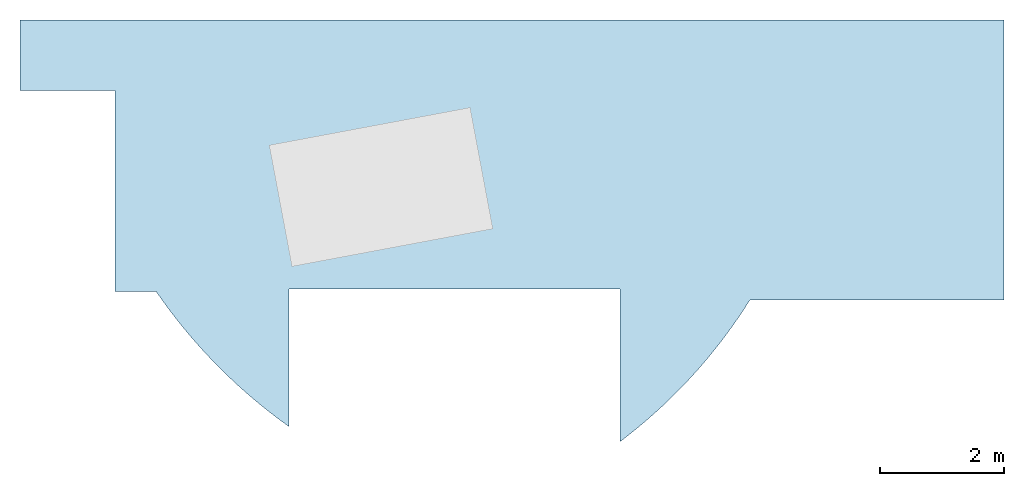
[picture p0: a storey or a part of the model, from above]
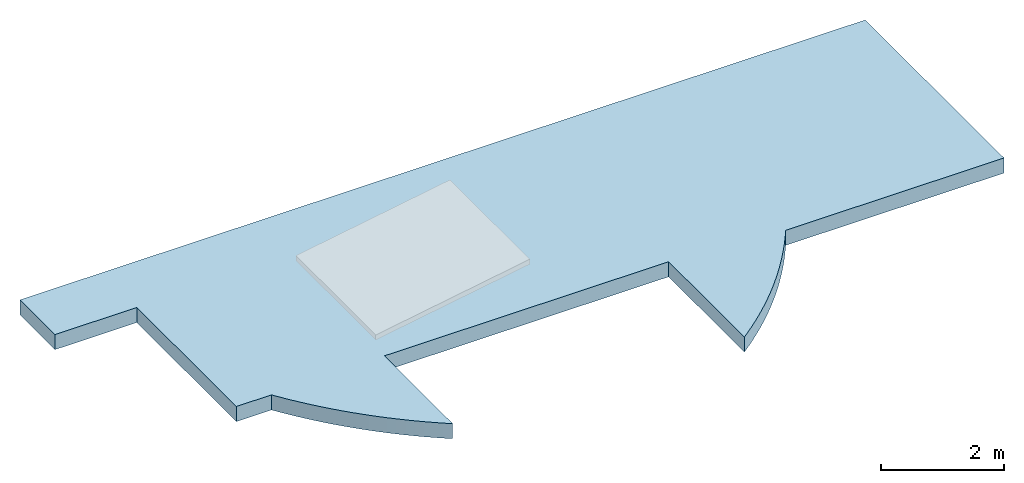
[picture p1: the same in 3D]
Properties of the parts of a building model (IFC4)

# File
Description: no view
File name: 20251114 LONDRES 55 HCB IFC.ifc
Time: 2025-11-14T18:05:01
Author: tecnic5
Organization: No Organization
Written by: ODA SDAI 25.4
Authorization: Usuari

# IfcBuildingStorey (22)
Name | In
PLANTA COBERTA | HABITATGE PLURIFAMILIAR | Elevation: 24.37 m
NOU | PLANTA COBERTA
PLANTA SOTACOBERTA | HABITATGE PLURIFAMILIAR | Elevation: 21.2 m
NOU | PLANTA SOTACOBERTA
PLANTA CINQUENA | HABITATGE PLURIFAMILIAR | Elevation: 18.29 m
NOU | PLANTA CINQUENA
PLANTA QUARTA | HABITATGE PLURIFAMILIAR | Elevation: 15.28 m
NOU | PLANTA QUARTA
PLANTA TERCERA | HABITATGE PLURIFAMILIAR | Elevation: 12.27 m
NOU | PLANTA TERCERA
PLANTA SEGONA | HABITATGE PLURIFAMILIAR | Elevation: 9.26 m
NOU | PLANTA SEGONA
PLANTA PRIMERA | HABITATGE PLURIFAMILIAR | Elevation: 6.25 m
NOU | PLANTA PRIMERA
PLANTA ALTELL | HABITATGE PLURIFAMILIAR | Elevation: 3.35 m
NOU | PLANTA ALTELL
PLANTA BAIXA | HABITATGE PLURIFAMILIAR | Elevation: 0 m
NOU | PLANTA BAIXA
PLANTA SOTERRANI -1 | HABITATGE PLURIFAMILIAR | Elevation: -3.37 m
NOU | PLANTA SOTERRANI -1
PLANTA SOTERRANI -2 | HABITATGE PLURIFAMILIAR | Elevation: -6.3 m
NOU | PLANTA SOTERRANI -2

# IfcBeam (2)
In: NOU
HCB_Identificacio - HCB_I1-CodiGuBIMclass: 20.20.20.20; HCB_I2-DescripcioBIMclass: Jàsseres; HCB_I3-TipusNom: Jàssera; HCB_I4-Subsistema: ARQ
Pset_BeamCommon - Status: EXISTING
Name
Jàssera PSC
Jàssera PS-2

# IfcBuildingElementProxy (38)
In: NOU
Name | HCB_I1-CodiGuBIMclass | HCB_I2-DescripcioBIMclass | HCB_I3-TipusNom | HCB_I4-Subsistema | Status
3 x Mirall P5 | 60.20.10.60 | Miralls | Mirall | ARQ | EXISTING
Porta P5 | 40.10.10.40 | Fusteria interior | FUS_Porta | ARQ | NEW
3 x Mirall P4 | 60.20.10.60 | Miralls | Mirall | ARQ | EXISTING
Porta P4 | 40.10.10.40 | Fusteria interior | FUS_Porta | ARQ | NEW
3 x Mirall P3 | 60.20.10.60 | Miralls | Mirall | ARQ | EXISTING
Porta P3 | 40.10.10.40 | Fusteria interior | FUS_Porta | ARQ | NEW
3 x Mirall P2 | 60.20.10.60 | Miralls | Mirall | ARQ | EXISTING
2 x Porta P2 | 40.10.10.40 | Fusteria interior | FUS_Porta | ARQ | NEW
2 x Taula redona 1.2m
3 x Mirall P1 | 60.20.10.60 | Miralls | Mirall | ARQ | EXISTING
2 x Inodor P1 | 60.10.10.10 | Inodors | Inodor | ARQ | EXISTING
Porta exterior P1 | 30.10.20.20 | Portes de façanes | Porta de façana | ARQ | EXISTING
Porta P1 | 40.10.10.40 | Fusteria interior | FUS_Porta | ARQ | NEW
4 x Mirall PA | 60.20.10.60 | Miralls | Mirall | ARQ | EXISTING
3 x Nuevo macro (8)
Porta PA | 40.10.10.40 | Fusteria interior | FUS_Porta | ARQ | NEW
2 x Mirall PB | 60.20.10.60 | Miralls | Mirall | ARQ | EXISTING
Mirall PB | 60.20.10.60 | Miralls | Mirall | ARQ | NEW
Porta PB | 40.10.10.40 | Fusteria interior | FUS_Porta | ARQ | NEW

# IfcColumn (159)
In: NOU
PredefinedType: COLUMN
HCB_Identificacio - HCB_I1-CodiGuBIMclass: 20.20.10.10; HCB_I2-DescripcioBIMclass: Pilars; HCB_I3-TipusNom: Pilar; HCB_I4-Subsistema: ARQ
Pset_ColumnCommon - Status: EXISTING
Name
17 x Pilar P5
17 x Pilar P4
17 x Pilar P3
17 x Pilar P2
17 x Pilar P1
20 x Pilar PA
18 x Pilar PB
18 x Pilar PS-1
18 x Pilar PS-2

# IfcDoor (203)
In: NOU
PredefinedType: DOOR; OperationType: USERDEFINED
AllplanQuantities - GlassSurface: 0; HeightWindowSillOutside: 0; HeightWindowSillInside: 0; OffsetOpeningBottom: 0; OffsetOpeningTop: 0; OffsetOpeningLeft: 0; OffsetOpeningRight: 0; DeductionOpeningBottom: 0
HCB_Identificacio - HCB_I4-Subsistema: ARQ
Name | OverallHeight (m) | OverallWidth (m) | DeductionOpeningLeft = DeductionOpeningRight | DeductionOpeningTop | HCB_I1-CodiGuBIMclass | HCB_I2-DescripcioBIMclass | HCB_I3-TipusNom | Status
Porta PSC | 2.15 | 0.94 | 70 | 70 | 30.10.20.20 | Portes de façanes | Porta de façana | EXISTING
Porta PSC | 2.15 | 0.91 | 70 | 70 | 40.10.10.40 | Fusteria interior | FUS_Porta | EXISTING
Porta PSC | 2.15 | 0.83 | 70 | 70 | 40.10.10.40 | Fusteria interior | FUS_Porta | EXISTING
Porta PSC | 2.15 | 0.85 | 70 | 70 | 40.10.10.40 | Fusteria interior | FUS_Porta | EXISTING
Porta PSC | 2.15 | 0.90716 | 70 | 70 | 30.10.20.20 | Portes de façanes | Porta de façana | EXISTING
Porta P5 | 2.15 | 1.7991 | 70 | 70 | 40.10.10.40 | Fusteria interior | FUS_Porta | EXISTING
Porta P5 | 2.15 | 1.7383 | 70 | 70 | 40.10.10.40 | Fusteria interior | FUS_Porta | EXISTING
Porta P5 | 2.15 | 1.33 | 70 | 70 | 40.10.10.40 | Fusteria interior | FUS_Porta | EXISTING
Porta P5 | 2.15 | 1.23 | 70 | 70 | 40.10.10.40 | Fusteria interior | FUS_Porta | EXISTING
Porta P5 | 2.15 | 0.85 | 70 | 70 | 40.10.10.40 | Fusteria interior | FUS_Porta | EXISTING
Porta P5 | 2.15 | 0.76332 | 50 | 50 | 40.10.10.40 | Fusteria interior | FUS_Porta | EXISTING
7 x Porta P5 | 2.15 | 0.94 | 70 | 70 | 40.10.10.40 | Fusteria interior | FUS_Porta | NEW
5 x Porta PA | 2.15 | 0.82267 | 30 | 30 | 40.10.10.40 | Fusteria interior | FUS_Porta | EXISTING
2 x Porta P4 | 2.15 | 0.44193 | 30 | 30 | 40.10.10.40 | Fusteria interior | FUS_Porta | NEW
Porta P5 | 2.15 | 0.74152 | 70 | 70 | 40.10.10.40 | Fusteria interior | FUS_Porta | NEW
Porta P5 | 2.15 | 0.73897 | 70 | 70 | 40.10.10.40 | Fusteria interior | FUS_Porta | NEW
Porta P5 | 2.15 | 1 | 70 | 70 | 40.10.10.40 | Fusteria interior | FUS_Porta | EXISTING
Porta P5 | 2.15 | 0.9 | 0 | 0 | 40.10.10.40 | Fusteria interior | FUS_Porta | NEW
Porta P5 | 2.15 | 1.02087 | 70 | 70 | 40.10.10.40 | Fusteria interior | FUS_Porta | NEW
Porta P4 | 2.15 | 1.73842 | 70 | 70 | 40.10.10.40 | Fusteria interior | FUS_Porta | EXISTING
Porta P4 | 2.15 | 1.32905 | 70 | 70 | 40.10.10.40 | Fusteria interior | FUS_Porta | EXISTING
Porta P4 | 2.15 | 1.23 | 70 | 70 | 40.10.10.40 | Fusteria interior | FUS_Porta | EXISTING
Porta P4 | 2.15 | 1.7991 | 70 | 70 | 40.10.10.40 | Fusteria interior | FUS_Porta | EXISTING
Porta P4 | 2.15 | 0.76751 | 50 | 50 | 40.10.10.40 | Fusteria interior | FUS_Porta | EXISTING
Porta P4 | 2.15 | 0.84771 | 70 | 70 | 40.10.10.40 | Fusteria interior | FUS_Porta | EXISTING
Porta P4 | 2.15 | 0.73897 | 70 | 70 | 40.10.10.40 | Fusteria interior | FUS_Porta | NEW
Porta P4 | 2.15 | 0.74 | 70 | 70 | 40.10.10.40 | Fusteria interior | FUS_Porta | NEW
Porta P4 | 2.15 | 1 | 70 | 70 | 40.10.10.40 | Fusteria interior | FUS_Porta | NEW
Porta P4 | 2.15 | 0.9 | 0 | 0 | 40.10.10.40 | Fusteria interior | FUS_Porta | NEW
Porta P4 | 2.15 | 1.02087 | 70 | 70 | 40.10.10.40 | Fusteria interior | FUS_Porta | NEW
Porta P4 | 2.15 | 0.94 | 70 | 70 | 40.10.10.40 | Fusteria interior | FUS_Porta | EXISTING
3 x Porta P4 | 2.15 | 0.94 | 70 | 70 | 40.10.10.40 | Fusteria interior | FUS_Porta | NEW
Porta P3 | 2.15 | 1.73983 | 70 | 70 | 40.10.10.40 | Fusteria interior | FUS_Porta | EXISTING
Porta P3 | 2.71 | 1.23 | 70 | 70 | 40.10.10.40 | Fusteria interior | FUS_Porta | EXISTING
Porta P3 | 2.15 | 1.7991 | 70 | 70 | 40.10.10.40 | Fusteria interior | FUS_Porta | EXISTING
Porta P3 | 2.71 | 0.85 | 70 | 70 | 40.10.10.40 | Fusteria interior | FUS_Porta | EXISTING
Porta P3 | 2.15 | 1.33 | 70 | 70 | 40.10.10.40 | Fusteria interior | FUS_Porta | EXISTING
Porta P3 | 2.15 | 0.76332 | 50 | 50 | 40.10.10.40 | Fusteria interior | FUS_Porta | EXISTING
Porta P3 | 2.15 | 0.99903 | 70 | 70 | 40.10.10.40 | Fusteria interior | FUS_Porta | NEW
Porta P3 | 2.71 | 0.77103 | 70 | 70 | 40.10.10.40 | Fusteria interior | FUS_Porta | NEW
Porta P3 | 2.15 | 0.74 | 70 | 70 | 40.10.10.40 | Fusteria interior | FUS_Porta | NEW
8 x Porta P3 | 2.15 | 0.94 | 70 | 70 | 40.10.10.40 | Fusteria interior | FUS_Porta | NEW
Porta P3 | 2.3 | 0.88801 | 70 | 70 | 40.10.10.40 | Fusteria interior | FUS_Porta | NEW
Porta P3 | 2.71 | 0.9 | 0 | 0 | 40.10.10.40 | Fusteria interior | FUS_Porta | NEW
Porta P3 | 2.15 | 1.02664 | 70 | 70 | 40.10.10.40 | Fusteria interior | FUS_Porta | NEW
Porta P2 | 2.71 | 0.85 | 70 | 70 | 40.10.10.40 | Fusteria interior | FUS_Porta | EXISTING
Porta P2 | 2.71 | 1.73983 | 70 | 70 | 40.10.10.40 | Fusteria interior | FUS_Porta | EXISTING
Porta P2 | 2.71 | 1.22594 | 70 | 70 | 40.10.10.40 | Fusteria interior | FUS_Porta | EXISTING
Porta P2 | 2.71 | 1.33 | 70 | 70 | 40.10.10.40 | Fusteria interior | FUS_Porta | EXISTING
Porta P2 | 2.3 | 1.60014 | 70 | 70 | 40.10.10.40 | Fusteria interior | FUS_Porta | EXISTING
Porta P2 | 2.71 | 0.8061 | 50 | 50 | 40.10.10.40 | Fusteria interior | FUS_Porta | EXISTING
11 x Porta P2 | 2.3 | 0.94 | 70 | 70 | 40.10.10.40 | Fusteria interior | FUS_Porta | NEW
Porta P2 | 2.71 | 0.7 | 70 | 70 | 40.10.10.40 | Fusteria interior | FUS_Porta | NEW
Porta P2 | 2.71 | 0.74 | 70 | 70 | 40.10.10.40 | Fusteria interior | FUS_Porta | NEW
Porta P2 | 2.71 | 0.99903 | 70 | 70 | 40.10.10.40 | Fusteria interior | FUS_Porta | NEW
Porta P2 | 2.15 | 0.44193 | 30 | 70 | 40.10.10.40 | Fusteria interior | FUS_Porta | NEW
Porta P2 | 2.71 | 0.79577 | 0 | 0 | 40.10.10.40 | Fusteria interior | FUS_Porta | NEW
Porta P2 | 2.71 | 1.02087 | 70 | 70 | 40.10.10.40 | Fusteria interior | FUS_Porta | NEW
Porta P1 | 2.15 | 0.82523 | 70 | 70 | 40.10.10.40 | Fusteria interior | FUS_Porta | EXISTING
Porta P1 | 2.15 | 0.76751 | 70 | 70 | 40.10.10.40 | Fusteria interior | FUS_Porta | EXISTING
Porta P1 | 2.15 | 1.60127 | 70 | 70 | 40.10.10.40 | Fusteria interior | FUS_Porta | EXISTING
Porta P1 | 2.15 | 0.79017 | 50 | 50 | 40.10.10.40 | Fusteria interior | FUS_Porta | EXISTING
Porta P1 | 2.15 | 0.85 | 70 | 70 | 40.10.10.40 | Fusteria interior | FUS_Porta | EXISTING
Porta P1 | 2.15 | 1.33311 | 70 | 70 | 40.10.10.40 | Fusteria interior | FUS_Porta | EXISTING
Porta P1 | 2.15 | 1.23 | 70 | 70 | 40.10.10.40 | Fusteria interior | FUS_Porta | EXISTING
Porta P1 | 2.15 | 1.74 | 70 | 70 | 40.10.10.40 | Fusteria interior | FUS_Porta | EXISTING
Porta exterior P1 | 2.19 | 0.99904 | 70 | 70 | 30.10.20.20 | Portes de façanes | Porta de façana | EXISTING
13 x Porta P1 | 2.15 | 0.94 | 70 | 70 | 40.10.10.40 | Fusteria interior | FUS_Porta | NEW
Porta P1 | 2.15 | 0.9 | 70 | 70 | 40.10.10.40 | Fusteria interior | FUS_Porta | NEW
Porta P1 | 2.3 | 0.94 | 70 | 70 | 40.10.10.40 | Fusteria interior | FUS_Porta | NEW
2 x Porta P1 | 2.15 | 0.74 | 70 | 70 | 40.10.10.40 | Fusteria interior | FUS_Porta | NEW
Porta P1 | 2.15 | 0.99903 | 70 | 70 | 40.10.10.40 | Fusteria interior | FUS_Porta | NEW
Porta P1 | 2.15 | 0.44193 | 30 | 30 | 40.10.10.40 | Fusteria interior | FUS_Porta | NEW
Porta P1 | 2.15 | 0.79405 | 0 | 0 | 40.10.10.40 | Fusteria interior | FUS_Porta | NEW
Porta PA | 2.1 | 1.12 | 70 | 70 | 40.10.10.40 | Fusteria interior | FUS_Porta | EXISTING
Porta PA | 2.15 | 0.82833 | 30 | 30 | 40.10.10.40 | Fusteria interior | FUS_Porta | EXISTING
2 x Porta PA | 2.15 | 0.83919 | 30 | 30 | 40.10.10.40 | Fusteria interior | FUS_Porta | EXISTING
4 x Porta PA | 2.15 | 0.94 | 70 | 70 | 40.10.10.40 | Fusteria interior | FUS_Porta | EXISTING
Porta PA | 2.15 | 1.12999 | 70 | 70 | 40.10.10.40 | Fusteria interior | FUS_Porta | EXISTING
Porta PA | 2.15 | 1.20933 | 70 | 70 | 40.10.10.40 | Fusteria interior | FUS_Porta | EXISTING
Porta PA | 2.15 | 1.90909 | 70 | 70 | 40.10.10.40 | Fusteria interior | FUS_Porta | EXISTING
Porta PA | 2.15 | 0.85318 | 70 | 70 | 40.10.10.40 | Fusteria interior | FUS_Porta | EXISTING
Porta PA | 2.15 | 0.84999 | 70 | 70 | 40.10.10.40 | Fusteria interior | FUS_Porta | EXISTING
2 x Porta PA | 2.15 | 0.8525 | 30 | 30 | 40.10.10.40 | Fusteria interior | FUS_Porta | EXISTING
Porta PA | 2.15 | 0.855 | 30 | 30 | 40.10.10.40 | Fusteria interior | FUS_Porta | EXISTING
Porta PA | 2.15 | 0.85 | 30 | 30 | 40.10.10.40 | Fusteria interior | FUS_Porta | EXISTING
Porta PA | 2.15 | 0.89999 | 70 | 70 | 40.10.10.40 | Fusteria interior | FUS_Porta | EXISTING
4 x Porta PA | 2.15 | 0.74 | 70 | 70 | 40.10.10.40 | Fusteria interior | FUS_Porta | NEW
Porta PA | 2.15 | 1.04683 | 70 | 70 | 40.10.10.40 | Fusteria interior | FUS_Porta | NEW
2 x Porta PA | 2.1 | 0.9 | 0 | 0 | 40.10.10.40 | Fusteria interior | FUS_Porta | NEW
2 x Porta PA | 2.15 | 0.94 | 70 | 70 | 40.10.10.40 | Fusteria interior | FUS_Porta | NEW
Porta PA | 2.15 | 1.74 | 70 | 70 | 40.10.10.40 | Fusteria interior | FUS_Porta | NEW
Porta PB | 2.15 | 1.05109 | 70 | 70 | 40.10.10.40 | Fusteria interior | FUS_Porta | EXISTING
Porta PB | 2.15 | 0.9999 | 70 | 70 | 30.10.20.20 | Portes de façanes | Portes de façanes | EXISTING
Porta PB | 2.1 | 1.03905 | 0 | 0 | 40.10.10.40 | Fusteria interior | FUS_Porta | EXISTING
Porta PB | 2.15 | 1.12987 | 70 | 70 | 40.10.10.40 | Fusteria interior | FUS_Porta | EXISTING
Porta PB | 2.15 | 0.99992 | 70 | 70 | 40.10.10.40 | Fusteria interior | FUS_Porta | EXISTING
Porta PB | 2.15 | 1.99236 | 70 | 70 | 40.10.10.40 | Fusteria interior | FUS_Porta | EXISTING
Porta PB | 2.15 | 1.91908 | 70 | 70 | 40.10.10.40 | Fusteria interior | FUS_Porta | EXISTING
Porta PB | 2.1 | 0.7 | 70 | 70 | 40.10.10.40 | Fusteria interior | FUS_Porta | EXISTING
Porta PB | 2.15 | 1.08 | 70 | 70 | 40.10.10.40 | Fusteria interior | FUS_Porta | EXISTING
Porta PB | 2.1 | 0.69763 | 70 | 70 | 40.10.10.40 | Fusteria interior | FUS_Porta | EXISTING
Porta PB | 2.15 | 1.49475 | 70 | 70 | 40.10.10.40 | Fusteria interior | FUS_Porta | EXISTING
Porta PB | 2.15 | 1.34849 | 70 | 70 | 40.10.10.40 | Fusteria interior | FUS_Porta | EXISTING
Porta PB | 3.07 | 0.85 | 70 | 70 | 40.10.10.40 | Fusteria interior | FUS_Porta | EXISTING
Porta PB | 2.1 | 2.72844 | 0 | 0 | 40.10.10.40 | Fusteria interior | FUS_Porta | EXISTING
Porta PB | 2.15 | 1.40932 | 70 | 70 | 40.10.10.40 | Fusteria interior | FUS_Porta | EXISTING
Porta PB | 2.1 | 0.9 | 0 | 0 | 40.10.10.40 | Fusteria interior | FUS_Porta | NEW
Porta PB | 2.15 | 1.05 | 70 | 70 | 40.10.10.40 | Fusteria interior | FUS_Porta | NEW
Porta PB | 2.15 | 0.9 | 70 | 70 | 40.10.10.40 | Fusteria interior | FUS_Porta | NEW
Porta PB | 2.15 | 1.74 | 70 | 70 | 40.10.10.40 | Fusteria interior | FUS_Porta | NEW
Porta PB | 2.15 | 0.95 | 70 | 70 | 40.10.10.40 | Fusteria interior | FUS_Porta | NEW
Porta PB | 2.15 | 0.94971 | 70 | 70 | 40.10.10.40 | Fusteria interior | FUS_Porta | NEW
Porta PB | 2.15 | 0.7 | 70 | 70 | 40.10.10.40 | Fusteria interior | FUS_Porta | NEW
Porta PB | 2.15 | 0.80613 | 70 | 70 | 40.10.10.40 | Fusteria interior | FUS_Porta | NEW
Porta PB | 2.1 | 0.90163 | 0 | 0 | 40.10.10.40 | Fusteria interior | FUS_Porta | NEW
2 x Porta PS-1 | 2.15 | 0.85 | 70 | 70 | 40.10.10.40 | Fusteria interior | FUS_Porta | EXISTING
Porta PS-1 | 2.15 | 0.89933 | 70 | 70 | 40.10.10.40 | Fusteria interior | FUS_Porta | EXISTING
Porta PS-1 | 2.15 | 1.73972 | 70 | 70 | 40.10.10.40 | Fusteria interior | FUS_Porta | EXISTING
2 x Porta PS-1 | 2.15 | 0.69667 | 70 | 70 | 40.10.10.40 | Fusteria interior | FUS_Porta | EXISTING
Porta PS-1 | 2.15 | 0.87504 | 70 | 70 | 40.10.10.40 | Fusteria interior | FUS_Porta | EXISTING
2 x Porta PS-1 | 2.15 | 0.93991 | 70 | 70 | 40.10.10.40 | Fusteria interior | FUS_Porta | EXISTING
Porta PS-1 | 2.15 | 1.53689 | 70 | 70 | 40.10.10.40 | Fusteria interior | FUS_Porta | EXISTING
Porta PS-1 | 2.15 | 0.93733 | 70 | 70 | 40.10.10.40 | Fusteria interior | FUS_Porta | EXISTING
Porta PS-1 | 2.15 | 0.69878 | 70 | 70 | 40.10.10.40 | Fusteria interior | FUS_Porta | EXISTING
Porta PS-1 | 2.15 | 0.93937 | 70 | 70 | 40.10.10.40 | Fusteria interior | FUS_Porta | EXISTING
Porta PS-1 | 2.15 | 0.89989 | 70 | 70 | 40.10.10.40 | Fusteria interior | FUS_Porta | EXISTING
Porta PS-1 | 2.15 | 0.89637 | 70 | 70 | 40.10.10.40 | Fusteria interior | FUS_Porta | EXISTING
2 x Porta PS-1 | 2.15 | 0.9 | 70 | 70 | 40.10.10.40 | Fusteria interior | FUS_Porta | EXISTING
Porta PS-1 | 2.15 | 0.92 | 70 | 70 | 40.10.10.40 | Fusteria interior | FUS_Porta | EXISTING
Porta PS-1 | 2 | 3.86716 | 0 | 0 | 40.10.10.40 | Fusteria interior | FUS_Porta | EXISTING
Porta PS-1 | 2.15 | 0.9 | 70 | 70 | 40.10.10.40 | Fusteria interior | FUS_Porta | NEW
Porta PS-1 | 2.15 | 0.93872 | 70 | 70 | 40.10.10.40 | Fusteria interior | FUS_Porta | NEW
Porta PS-1 | 2.15 | 1.73694 | 70 | 70 | 40.10.10.40 | Fusteria interior | FUS_Porta | NEW
Porta PS-1 | 2.15 | 0.94 | 70 | 70 | 40.10.10.40 | Fusteria interior | FUS_Porta | NEW
Porta PS-2 | 2.15 | 2.59974 | 0 | 0 | 40.10.10.40 | Fusteria interior | FUS_Porta | EXISTING
Porta PS-2 | 2.15 | 0.8509 | 70 | 70 | 40.10.10.40 | Fusteria interior | FUS_Porta | EXISTING
2 x Porta PS-2 | 2.15 | 0.94 | 70 | 70 | 40.10.10.40 | Fusteria interior | FUS_Porta | EXISTING
Porta PS-2 | 2.15 | 0.86781 | 70 | 70 | 40.10.10.40 | Fusteria interior | FUS_Porta | EXISTING
Porta PS-2 | 2.15 | 2.57661 | 0 | 0 | 40.10.10.40 | Fusteria interior | FUS_Porta | EXISTING
Porta PS-2 | 2.15 | 0.87 | 70 | 70 | 40.10.10.40 | Fusteria interior | FUS_Porta | NEW
3 x Porta PS-2 | 2.15 | 0.94 | 70 | 70 | 40.10.10.40 | Fusteria interior | FUS_Porta | NEW
Porta PS-2 | 2.15 | 0.8611 | 70 | 70 | 40.10.10.40 | Fusteria interior | FUS_Porta | EXISTING

# IfcDoor: Finestra P1 (12)
In: NOU
Type - PredefinedType: DOOR; ParameterTakesPrecedence: no
OverallHeight: 2.19 m; OverallWidth: 1 m
AllplanQuantities - GlassSurface: 1.6212; HeightWindowSillOutside: 0; HeightWindowSillInside: 0; OffsetOpeningBottom: 0; OffsetOpeningTop: 0; OffsetOpeningLeft: 0; OffsetOpeningRight: 0; DeductionOpeningBottom: 70; DeductionOpeningLeft: 70; DeductionOpeningRight: 70; DeductionOpeningTop: 70
HCB_Identificacio - HCB_I1-CodiGuBIMclass: 30.10.20.10; HCB_I2-DescripcioBIMclass: Finestres de façanes; HCB_I3-TipusNom: FUS_Finestra; HCB_I4-Subsistema: ARQ
Pset_DoorCommon - Status: EXISTING

# IfcDoor: Finestra P2 (14)
In: NOU
Type - PredefinedType: DOOR; ParameterTakesPrecedence: no
OverallHeight: 2.19 m; OverallWidth: 1 m
AllplanQuantities - GlassSurface: 1.6212; HeightWindowSillOutside: 0; HeightWindowSillInside: 0; OffsetOpeningBottom: 0; OffsetOpeningTop: 0; OffsetOpeningLeft: 0; OffsetOpeningRight: 0; DeductionOpeningBottom: 70; DeductionOpeningLeft: 70; DeductionOpeningRight: 70; DeductionOpeningTop: 70
HCB_Identificacio - HCB_I1-CodiGuBIMclass: 30.10.20.10; HCB_I2-DescripcioBIMclass: Finestres de façanes; HCB_I3-TipusNom: FUS_Finestra; HCB_I4-Subsistema: ARQ
Pset_DoorCommon - Status: EXISTING

# IfcDoor: Finestra P3 (14)
In: NOU
Type - PredefinedType: DOOR; ParameterTakesPrecedence: no
OverallHeight: 2.19 m
AllplanQuantities - HeightWindowSillOutside: 0; HeightWindowSillInside: 0; OffsetOpeningBottom: 0; OffsetOpeningTop: 0; OffsetOpeningLeft: 0; OffsetOpeningRight: 0; DeductionOpeningBottom: 70; DeductionOpeningLeft: 70; DeductionOpeningRight: 70; DeductionOpeningTop: 70
HCB_Identificacio - HCB_I1-CodiGuBIMclass: 30.10.20.10; HCB_I2-DescripcioBIMclass: Finestres de façanes; HCB_I3-TipusNom: FUS_Finestra; HCB_I4-Subsistema: ARQ
Pset_DoorCommon - Status: EXISTING
Name | OverallWidth (m) | GlassSurface
7 x Finestra P3 | 1 | 1.6212
Finestra P3 | 0.98216 | 1.58571
5 x Finestra P3 | 0.98352 | 1.58843
Finestra P3 | 0.99513 | 1.61152

# IfcDoor: Finestra P4 (14)
In: NOU
Type - PredefinedType: DOOR; ParameterTakesPrecedence: no
OverallHeight: 2.19 m; OverallWidth: 0.98352 m
AllplanQuantities - GlassSurface: 1.58843; HeightWindowSillOutside: 0; HeightWindowSillInside: 0; OffsetOpeningBottom: 0; OffsetOpeningTop: 0; OffsetOpeningLeft: 0; OffsetOpeningRight: 0; DeductionOpeningBottom: 70; DeductionOpeningLeft: 70; DeductionOpeningRight: 70; DeductionOpeningTop: 70
HCB_Identificacio - HCB_I1-CodiGuBIMclass: 30.10.20.10; HCB_I2-DescripcioBIMclass: Finestres de façanes; HCB_I3-TipusNom: FUS_Finestra; HCB_I4-Subsistema: ARQ
Pset_DoorCommon - Status: EXISTING

# IfcDoor: Finestra P5 (14)
In: NOU
Type - PredefinedType: DOOR; ParameterTakesPrecedence: no
OverallHeight: 2.19 m
AllplanQuantities - HeightWindowSillOutside: 0; HeightWindowSillInside: 0; OffsetOpeningBottom: 0; OffsetOpeningTop: 0; OffsetOpeningLeft: 0; OffsetOpeningRight: 0; DeductionOpeningBottom: 70; DeductionOpeningLeft: 70; DeductionOpeningRight: 70; DeductionOpeningTop: 70
HCB_Identificacio - HCB_I1-CodiGuBIMclass: 30.10.20.10; HCB_I2-DescripcioBIMclass: Finestres de façanes; HCB_I3-TipusNom: FUS_Finestra; HCB_I4-Subsistema: ARQ
Pset_DoorCommon - Status: EXISTING
Name | OverallWidth (m) | GlassSurface
10 x Finestra P5 | 1 | 1.6212
Finestra P5 | 0.99855 | 1.61831
2 x Finestra P5 | 0.98352 | 1.58843
Finestra P5 | 0.99632 | 1.61389

# IfcDoor: Finestra PSC
In: NOU
Type - PredefinedType: DOOR; ParameterTakesPrecedence: no
OverallHeight: 0.55 m; OverallWidth: 8.16309 m
AllplanQuantities - GlassSurface: 3.28947; HeightWindowSillOutside: 0; HeightWindowSillInside: 0; OffsetOpeningBottom: 0; OffsetOpeningTop: 0; OffsetOpeningLeft: 0; OffsetOpeningRight: 0; DeductionOpeningBottom: 70; DeductionOpeningLeft: 70; DeductionOpeningRight: 70; DeductionOpeningTop: 70
HCB_Identificacio - HCB_I1-CodiGuBIMclass: 30.10.20.10; HCB_I2-DescripcioBIMclass: Finestres de façanes; HCB_I3-TipusNom: FUS_Finestra; HCB_I4-Subsistema: ARQ
Pset_DoorCommon - Status: EXISTING

# IfcDoor: Porta P1
In: NOU
Type - PredefinedType: DOOR; ParameterTakesPrecedence: no
OverallHeight: 2.15 m; OverallWidth: 0.63 m
AllplanQuantities - GlassSurface: 0.9849; HeightWindowSillOutside: 0; HeightWindowSillInside: 0; OffsetOpeningBottom: 0; OffsetOpeningTop: 0; OffsetOpeningLeft: 0; OffsetOpeningRight: 0; DeductionOpeningBottom: 70; DeductionOpeningLeft: 70; DeductionOpeningRight: 70; DeductionOpeningTop: 70
HCB_Identificacio - HCB_I1-CodiGuBIMclass: 40.10.10.40; HCB_I2-DescripcioBIMclass: Fusteria interior; HCB_I3-TipusNom: FUS_Porta; HCB_I4-Subsistema: ARQ
Pset_DoorCommon - Status: EXISTING

# IfcDoor: Porta P2
In: NOU
Type - PredefinedType: DOOR; ParameterTakesPrecedence: no
OverallHeight: 2.71 m; OverallWidth: 0.68154 m
AllplanQuantities - GlassSurface: 1.39176; HeightWindowSillOutside: 0; HeightWindowSillInside: 0; OffsetOpeningBottom: 0; OffsetOpeningTop: 0; OffsetOpeningLeft: 0; OffsetOpeningRight: 0; DeductionOpeningBottom: 70; DeductionOpeningLeft: 70; DeductionOpeningRight: 70; DeductionOpeningTop: 70
HCB_Identificacio - HCB_I1-CodiGuBIMclass: 40.10.10.40; HCB_I2-DescripcioBIMclass: Fusteria interior; HCB_I3-TipusNom: FUS_Porta; HCB_I4-Subsistema: ARQ
Pset_DoorCommon - Status: EXISTING

# IfcDoor: Porta P3
In: NOU
Type - PredefinedType: DOOR; ParameterTakesPrecedence: no
OverallHeight: 2.15 m; OverallWidth: 0.68 m
AllplanQuantities - GlassSurface: 1.0854; HeightWindowSillOutside: 0; HeightWindowSillInside: 0; OffsetOpeningBottom: 0; OffsetOpeningTop: 0; OffsetOpeningLeft: 0; OffsetOpeningRight: 0; DeductionOpeningBottom: 70; DeductionOpeningLeft: 70; DeductionOpeningRight: 70; DeductionOpeningTop: 70
HCB_Identificacio - HCB_I1-CodiGuBIMclass: 40.10.10.40; HCB_I2-DescripcioBIMclass: Fusteria interior; HCB_I3-TipusNom: FUS_Porta; HCB_I4-Subsistema: ARQ
Pset_DoorCommon - Status: EXISTING

# IfcDoor: Porta P4
In: NOU
Type - PredefinedType: DOOR; ParameterTakesPrecedence: no
OverallHeight: 2.15 m; OverallWidth: 0.68 m
AllplanQuantities - GlassSurface: 1.0854; HeightWindowSillOutside: 0; HeightWindowSillInside: 0; OffsetOpeningBottom: 0; OffsetOpeningTop: 0; OffsetOpeningLeft: 0; OffsetOpeningRight: 0; DeductionOpeningBottom: 70; DeductionOpeningLeft: 70; DeductionOpeningRight: 70; DeductionOpeningTop: 70
HCB_Identificacio - HCB_I1-CodiGuBIMclass: 40.10.10.40; HCB_I2-DescripcioBIMclass: Fusteria interior; HCB_I3-TipusNom: FUS_Porta; HCB_I4-Subsistema: ARQ
Pset_DoorCommon - Status: EXISTING

# IfcDoor: Porta P5
In: NOU
Type - PredefinedType: DOOR; ParameterTakesPrecedence: no
OverallHeight: 2.15 m; OverallWidth: 0.67699 m
AllplanQuantities - GlassSurface: 1.07936; HeightWindowSillOutside: 0; HeightWindowSillInside: 0; OffsetOpeningBottom: 0; OffsetOpeningTop: 0; OffsetOpeningLeft: 0; OffsetOpeningRight: 0; DeductionOpeningBottom: 70; DeductionOpeningLeft: 70; DeductionOpeningRight: 70; DeductionOpeningTop: 70
HCB_Identificacio - HCB_I1-CodiGuBIMclass: 40.10.10.40; HCB_I2-DescripcioBIMclass: Fusteria interior; HCB_I3-TipusNom: FUS_Porta; HCB_I4-Subsistema: ARQ
Pset_DoorCommon - Status: EXISTING

# IfcDoor: Porta PA
In: NOU
Type - PredefinedType: DOOR; OperationType: SINGLE_SWING_RIGHT; ParameterTakesPrecedence: no
Type - IfcDoorLiningProperties - LiningDepth: 0.03 m; LiningThickness: 0.03 m
OverallHeight: 2.15 m; OverallWidth: 0.44193 m
AllplanQuantities - GlassSurface: 0.663178; HeightWindowSillOutside: 0; HeightWindowSillInside: 0; OffsetOpeningBottom: 0; OffsetOpeningTop: 0; OffsetOpeningLeft: 0; OffsetOpeningRight: 0; DeductionOpeningBottom: 0; DeductionOpeningLeft: 30; DeductionOpeningRight: 30; DeductionOpeningTop: 30
HCB_Identificacio - HCB_I1-CodiGuBIMclass: 40.10.10.40; HCB_I2-DescripcioBIMclass: Fusteria interior; HCB_I3-TipusNom: FUS_Porta; HCB_I4-Subsistema: ARQ
Pset_DoorCommon - Status: EXISTING

# IfcDoor: Porta PB (4)
In: NOU
Type - PredefinedType: DOOR; OperationType: SINGLE_SWING_RIGHT; ParameterTakesPrecedence: no
Type - IfcDoorLiningProperties - LiningDepth: 0.07 m; LiningThickness: 0.07 m
OverallHeight: 2.15 m
AllplanQuantities - HeightWindowSillOutside: 0; HeightWindowSillInside: 0; OffsetOpeningBottom: 0; OffsetOpeningTop: 0; OffsetOpeningLeft: 0; OffsetOpeningRight: 0; DeductionOpeningBottom: 0; DeductionOpeningLeft: 70; DeductionOpeningRight: 70; DeductionOpeningTop: 70
HCB_Identificacio - HCB_I4-Subsistema: ARQ
Name | OverallWidth (m) | GlassSurface | HCB_I1-CodiGuBIMclass | HCB_I2-DescripcioBIMclass | HCB_I3-TipusNom | Status
Porta PB | 1.06881 | 1.755 | 30.10.20.20 | Portes de façanes | Porta de façana | EXISTING
3 x Porta PB | 0.94 | 1.4948 | 40.10.10.40 | Fusteria interior | FUS_Porta | NEW

# IfcDoor: Reixeta de ventilació PA (3)
In: NOU
Type - PredefinedType: DOOR; ParameterTakesPrecedence: no
OverallHeight: 0.9 m
AllplanQuantities - GlassSurface: 0; HeightWindowSillOutside: 0; HeightWindowSillInside: 0; OffsetOpeningBottom: 0; OffsetOpeningTop: 0; OffsetOpeningLeft: 0; OffsetOpeningRight: 0; DeductionOpeningBottom: 70; DeductionOpeningLeft: 70; DeductionOpeningRight: 70; DeductionOpeningTop: 70
HCB_Identificacio - HCB_I1-CodiGuBIMclass: 40.10.10.40; HCB_I2-DescripcioBIMclass: Fusteria interior; HCB_I3-TipusNom: FUS_Reixeta de ventilació; HCB_I4-Subsistema: ARQ
Pset_DoorCommon - Status: EXISTING
Name | OverallWidth (m)
2 x Reixeta de ventilació PA | 1.04747
Reixeta de ventilació PA | 1.8666

# IfcFurniture (1097)
In: NOU
HCB_Identificacio - HCB_I4-Subsistema: ARQ
Name | HCB_I1-CodiGuBIMclass | HCB_I2-DescripcioBIMclass | HCB_I3-TipusNom
Placa solar PC | 60.20.10.80 | Altres mobiliaris fixes | Placa solar | Pset_FurnitureTypeCommon - Status: EXISTING
4 x Inodor P4 | 60.10.10.10 | Inodors | Inodor | Pset_FurnitureTypeCommon - Status: EXISTING
3 x Rentamans P5 | 60.10.10.60 | Rentamans | Rentamans | Pset_FurnitureTypeCommon - Status: EXISTING
2 x Inodor P5 | 60.10.10.10 | Inodors | Inodor | Pset_FurnitureTypeCommon - Status: EXISTING
Abocador P5 | 60.10.10.100 | Abocador | Abocador | Pset_FurnitureTypeCommon - Status: EXISTING
64 x Armai 60x60x60_P5 | 60.20.30.60 | Armaris, calaixeres i arxivadors | Armaris
55 x Taula 140X80_P5 | 60.20.30.10 | Taules | Taules
57 x Cadira d'Oficina_P5 | 60.20.30.20 | Cadires i sofàs | Cadires
Taula 200X120_P5 | 60.20.30.10 | Taules | Taules
10 x Cadira confident_P5 | 60.20.30.20 | Cadires i sofàs | Cadires
2 x Taula 140X60_P5 | 60.20.30.10 | Taules | Taules
3 x Rentamans P4 | 60.10.10.60 | Rentamans | Rentamans | Pset_FurnitureTypeCommon - Status: EXISTING
Abocador P4 | 60.10.10.100 | Abocador | Abocador | Pset_FurnitureTypeCommon - Status: EXISTING
44 x Taula 140X80_P4 | 60.20.30.10 | Taules | Taules
Taula 200X120_P4 | 60.20.30.10 | Taules | Taules
Taula 160X80_P4 | 60.20.30.10 | Taules | Taules
Taula 100X60_P4 | 60.20.30.10 | Taules | Taules
138 x Armai 60x60x60_P4 | 60.20.30.60 | Armaris, calaixeres i arxivadors | Armaris
3 x Taula 120X80_P4 | 60.20.30.10 | Taules | Taules
48 x Cadira d'Oficina_P4 | 60.20.30.20 | Cadires i sofàs | Cadires
8 x Cadira confident_P4 | 60.20.30.20 | Cadires i sofàs | Cadires
3 x Rentamans P3 | 60.10.10.60 | Rentamans | Rentamans | Pset_FurnitureTypeCommon - Status: EXISTING
3 x Inodor P3 | 60.10.10.10 | Inodors | Inodor | Pset_FurnitureTypeCommon - Status: EXISTING
Abocador P3 | 60.10.10.100 | Abocador | Abocador | Pset_FurnitureTypeCommon - Status: EXISTING
26 x Taula 140X80_P3 | 60.20.30.10 | Taules | Taules
4 x Taula D120_P3 | 60.20.30.10 | Taules | Taules
7 x Taula 160X80_P3 | 60.20.30.10 | Taules | Taules
7 x Taula 100X60_P3 | 60.20.30.10 | Taules | Taules
5 x Armai 80x45_P3 | 60.20.30.60 | Armaris, calaixeres i arxivadors | Armaris
18 x Armai 60x60x60_P3 | 60.20.30.60 | Armaris, calaixeres i arxivadors | Armaris
Taula 200X120_P3 | 60.20.30.10 | Taules | Taules
34 x Cadira confident_P3 | 60.20.30.20 | Cadires i sofàs | Cadires
32 x Cadira d'Oficina_P3 | 60.20.30.20 | Cadires i sofàs | Cadires
Taula D100_P3 | 60.20.30.10 | Taules | Taules
3 x Rentamans P2 | 60.10.10.60 | Rentamans | Rentamans | Pset_FurnitureTypeCommon - Status: EXISTING
3 x Inodor P2 | 60.10.10.10 | Inodors | Inodor | Pset_FurnitureTypeCommon - Status: EXISTING
Abocador P2 | 60.10.10.100 | Abocador | Abocador | Pset_FurnitureTypeCommon - Status: EXISTING
38 x Taula 140X80_P2 | 60.20.30.10 | Taules | Taules
3 x Taula 100X60_P2 | 60.20.30.10 | Taules | Taules
3 x Taula 160X80_P2 | 60.20.30.10 | Taules | Taules
2 x Taula D120_P2 | 60.20.30.10 | Taules | Taules
4 x Armai 80x45_P2 | 60.20.30.60 | Armaris, calaixeres i arxivadors | Armaris
41 x Cadira d'Oficina_P2 | 60.20.30.20 | Cadires i sofàs | Cadires
Taula 240X120_P3 | 60.20.30.10 | Taules | Taules
25 x Cadira confident_P2 | 60.20.30.20 | Cadires i sofàs | Cadires
3 x Rentamans P1 | 60.10.10.60 | Rentamans | Rentamans | Pset_FurnitureTypeCommon - Status: EXISTING
Inodor P1 | 60.10.10.10 | Inodors | Inodor | Pset_FurnitureTypeCommon - Status: EXISTING
Abocador P1 | 60.10.10.100 | Abocador | Abocador | Pset_FurnitureTypeCommon - Status: EXISTING
22 x Taula 140X80_P1 | 60.20.30.10 | Taules | Taules
9 x Taula 120X80_P1 | 60.20.30.10 | Taules | Taules
6 x Taula 160X80_P1 | 60.20.30.10 | Taules | Taules
16 x Taula 100X60_P1 | 60.20.30.10 | Taules | Taules
39 x Cadira d'Oficina_P1 | 60.20.30.20 | Cadires i sofàs | Cadires
25 x Cadira confient_P1 | 60.20.30.20 | Cadires i sofàs | Cadires
Taula 100X80_P1 | 60.20.30.10 | Taules | Taules
Armai 80x45 | 60.20.30.60 | Armaris, calaixeres i arxivadors | Armaris
2 x Taula D100_P1 | 60.20.30.10 | Taules | Taules
5 x Inodor PA | 60.10.10.10 | Inodors | Inodor | Pset_FurnitureTypeCommon - Status: EXISTING
4 x Rentamans PA | 60.10.10.60 | Rentamans | Rentamans | Pset_FurnitureTypeCommon - Status: EXISTING
Abocador PA | 60.10.10.100 | Abocador | Abocador | Pset_FurnitureTypeCommon - Status: NEW
15 x Taula 140X80_PA | 60.20.30.10 | Taules | Taules
2 x Taula 160X80_PA | 60.20.30.10 | Taules | Taules
Taula 120X80_PA | 60.20.30.10 | Taules | Taules
Taula 100X60_PA | 60.20.30.10 | Taules | Taules
Taula D100_PA | 60.20.30.10 | Taules | Taules
3 x Armai 160x45_PA | 60.20.30.60 | Armaris, calaixeres i arxivadors | Armaris
Piques_PA | 60.10.10.70 | Piques | Piques
4 x Taulells_PA | 60.20.10.10 | Taulells | Taulells
12 x Cadira d'Oficina_PA | 60.20.30.20 | Cadires i sofàs | Cadires
83 x Cadira confident_PA | 60.20.30.20 | Cadires i sofàs | Cadires
11 x Taula 80X70_PA | 60.20.30.10 | Taules | Taules
Taula 100X80_PA | 60.20.30.10 | Taules | Taules
Rentamans PB | 60.10.10.60 | Rentamans | Rentamans | Pset_FurnitureTypeCommon - Status: NEW
2 x Inodor PB | 60.10.10.10 | Inodors | Inodor | Pset_FurnitureTypeCommon - Status: NEW
2 x Rentamans PB | 60.10.10.60 | Rentamans | Rentamans | Pset_FurnitureTypeCommon - Status: EXISTING
2 x Inodor PB | 60.10.10.10 | Inodors | Inodor | Pset_FurnitureTypeCommon - Status: EXISTING
Abocador PB | 60.10.10.100 | Abocador | Abocador | Pset_FurnitureTypeCommon - Status: EXISTING
Taula D120_PB | 60.20.30.10 | Taules | Taules
3 x Armai 160x45_PB | 60.20.30.60 | Armaris, calaixeres i arxivadors | Armaris
Taula 240X120_PB | 60.20.30.10 | Taules | Taules
6 x Taula 100X100_PB | 60.20.30.10 | Taules | Taules
2 x Taula 140X80_PB | 60.20.30.10 | Taules | Taules
63 x Cadira confident_PB | 60.20.30.20 | Cadires i sofàs | Cadires
12 x Taula 80X70_PB | 60.20.30.10 | Taules | Taules
Mostrador 380X80_PB | 60.20.30.10 | Taules | Taules
Taula 100X80_PB | 60.20.30.10 | Taules | Taules
2 x Inodor PS-1 | 60.10.10.10 | Inodors | Inodor | Pset_FurnitureTypeCommon - Status: EXISTING
4 x Plats de dutxa PS-1 | 60.10.10.40 | Plats de dutxa | Plats de dutxa | Pset_FurnitureTypeCommon - Status: EXISTING
4 x Mirall PS-1 | 60.20.10.60 | Miralls | Mirall | Pset_FurnitureTypeCommon - Status: EXISTING
4 x Rentamans PS-1 | 60.10.10.60 | Rentamans | Rentamans | Pset_FurnitureTypeCommon - Status: EXISTING

# IfcOpeningElement: Opening (345)
In: NOU
Name | Status
5 x Vano finestra PSC | EXISTING
6 x Vano porta PSC | EXISTING
2 x Vano ventana | EXISTING
13 x Vano porta P5 | EXISTING
Vano de Finestra P5 | EXISTING
14 x Vano finestra P5 | EXISTING
8 x Vano porta P5 | NEW
40 x Vano de puerta PA | EXISTING
27 x Vano puerta | EXISTING
Vano de Finestra P4 | EXISTING
14 x Vano porta P4 | EXISTING
14 x Vano finestra P4 | EXISTING
5 x Vano porta P4 | NEW
13 x Vano porta P3 | EXISTING
Vano de Finestra P3 | EXISTING
14 x Vano finestra P3 | EXISTING
11 x Vano porta P3 | NEW
Vano de Finestra P2 | EXISTING
14 x Vano finestra P2 | EXISTING
16 x Vano puerta | NEW
16 x Vano de puerta P1 | EXISTING
21 x Vano de Finestra P1 | EXISTING
16 x Vano de puerta P1 | NEW
3 x Vano dei finestra PA | EXISTING
Nicho en muro | NEW
Vano de finestra PA | EXISTING
4 x Vano de puerta PA | NEW
27 x Vano de puerta PB | EXISTING
8 x Vano de puerta PB | NEW
28 x Vano de puerta PS-1 | EXISTING

# IfcRailing (2)
In: NOU
HCB_Identificacio - HCB_I1-CodiGuBIMclass: 60.20.10.80; HCB_I2-DescripcioBIMclass: Altres mobiliaris fixes; HCB_I3-TipusNom: Barana; HCB_I4-Subsistema: ARQ
Pset_RailingCommon - Status: EXISTING
Name
Baranna PSC
Baranna PSC exterior

# IfcRoof (3)
In: NOU
HCB_Identificacio - HCB_I4-Subsistema: ARQ
Pset_RoofCommon - Status: EXISTING
Name | HCB_I1-CodiGuBIMclass | HCB_I2-DescripcioBIMclass | HCB_I3-TipusNom
Cobertura PC | 30.20.10.10 | Cobertes in-situ | Coberta
Cobertura de vidres PSC | 30.20.10.20 | Cobertes Pre-fabricades | Cobertura de vidres
Cobertura de vidres P1 | 30.20.10.30 | Sistemes especials de cobertes | Cobertura de vidres

# IfcSlab (65)
In: NOU
Name | PredefinedType | HCB_I1-CodiGuBIMclass | HCB_I2-DescripcioBIMclass | HCB_I3-TipusNom | HCB_I4-Subsistema | Status
Forjat PSC | FLOOR | 20.20.20.10 | Forjats | Forjat | ARQ | EXISTING
Paviment PSC | FLOOR | 20.20.20.20 | Paviments | Paviment | ARQ
3 x Fals sostre PSC |  | 20.20.20.10 | Falsos sostres interiors | Fals sostre | ARQ | NEW
Fals sostre PSC | FLOOR | 20.20.20.10 | Falsos sostres interiors | Fals sostre | ARQ | NEW
Forjat P5 | FLOOR | 20.20.20.10 | Forjats | Forjat | ARQ | EXISTING
Fals sostre P5 | FLOOR | 20.20.20.10 | Falsos sostres interiors | Fals sostre | ARQ | NEW
5 x Acabats de façanes P5 | FLOOR | 30.10.10.40 | Acabats de façanes | Acabats de façanes | ARQ | EXISTING
2 x Paviment P5 | FLOOR | 20.20.20.20 | Paviments | Paviment | ARQ | EXISTING
Forjat P4 | FLOOR | 20.20.20.10 | Forjats | Forjat | ARQ | EXISTING
Fals sostre P4 | FLOOR | 20.20.20.10 | Falsos sostres interiors | Fals sostre | ARQ | NEW
11 x  | FLOOR | 20.20.20.20 | Paviments | Paviment | ARQ | EXISTING
Paviment PSC | FLOOR | 20.20.20.20 | Paviments | Paviment | ARQ | EXISTING
Forjat P3 | FLOOR | 20.20.20.10 | Forjats | Forjat | ARQ | EXISTING
Fals sostre P3 | FLOOR | 20.20.20.10 | Falsos sostres interiors | Fals sostre | ARQ | NEW
2 x Paviment P3 | FLOOR | 20.20.20.20 | Paviments | Paviment | ARQ
Forjat P2 | FLOOR | 20.20.20.10 | Forjats | Forjat | ARQ | EXISTING
Fals sostre P2 | FLOOR | 20.20.20.10 | Falsos sostres interiors | Fals sostre | ARQ | NEW
 | FLOOR | 20.20.20.20 | Paviments | Paviment | ARQ | NEW
Paviment P2 | FLOOR | 20.20.20.20 | Paviments | Paviment | ARQ
Forjat P1 | FLOOR | 20.20.20.10 | Forjats | Forjat | ARQ | EXISTING
Fals sostre P1 | FLOOR | 20.20.20.10 | Falsos sostres interiors | Fals sostre | ARQ | NEW
2 x  | FLOOR |  |  |  |  | EXISTING
Paviment P1 | FLOOR | 20.20.20.20 | Paviments | Paviment | ARQ
3 x Forjat PA | FLOOR | 20.20.20.10 | Forjats | Forjat | ARQ | EXISTING
2 x Fals sostre PA | FLOOR | 20.20.20.10 | Falsos sostres interiors | Fals sostre | ARQ | NEW
Fals sostre PA | FLOOR | 20.20.20.10 | Falsos sostres interiors | Fals sostre | ARQ
2 x Forjat PA | FLOOR | 20.20.20.10 | Forjats | Forjat | ARQ
2 x Forjat PB | FLOOR | 20.20.20.10 | Forjats | Forjat | ARQ | EXISTING
2 x Fals sostre PB | FLOOR | 20.20.20.10 | Falsos sostres interiors | Fals sostre | ARQ | EXISTING
Fals sostre PB | FLOOR | 20.20.20.10 | Falsos sostres interiors | Fals sostre | ARQ | NEW
2 x  | FLOOR | 30.40.10.10 | Graons exteriors | Graons | ARQ | EXISTING
 | FLOOR | 20.20.10.50 | Rampes d´estructura | Rampa | ARQ | EXISTING
 | FLOOR | 20.20.20.20 | Paviments | Paviment | ARQ
3 x Forjat PS-1 | FLOOR | 20.20.20.10 | Forjats | Forjat | ARQ | EXISTING
Fals sostre PS-1 | FLOOR | 20.20.20.10 | Falsos sostres interiors | Fals sostre | ARQ | EXISTING
 | FLOOR | 20.20.20.10 | Forjats | Esth_Forjat | ARQ | EXISTING
 | FLOOR | 20.10.40.10 | Soleres | Bas_Sol | ARQ | EXISTING

# IfcStair (20)
In: NOU
Name | HCB_I1-CodiGuBIMclass | HCB_I2-DescripcioBIMclass | HCB_I3-TipusNom | HCB_I4-Subsistema | Status | NumberOfRiser | RiserHeight (m) | TreadLength (m)
Escala PSC | 20.20.10.40 | Escales d´estructura | Escala | ARQ | EXISTING | 4 | 0.17 | 0.3
Peldaño final | 20.20.10.40 | Escales d´estructura | Escala | ARQ | EXISTING | 17 | 0.171 | 0.285 | PredefinedType: USERDEFINED; Material: *varios*; Pset_StairCommon - RequiredHeadroom: 2 m; WalkingLineOffset: 0.575 m; TreadLengthAtOffset: 0.285 m; WaistThickness: 0.17 m; NosingLength: 0 m; TreadLengthAtInnerSide: 0.1 m; NumberOfTreads: 17
Escala P4 | 20.20.10.40 | Escales d´estructura | Escala | ARQ | EXISTING | 17 | 0.177 | 0.285
Escala P3 | 20.20.10.40 | Escales d´estructura | Escala | ARQ | EXISTING | 17 | 0.177 | 0.285
Escala P2 | 20.20.10.40 | Escales d´estructura | Escala | ARQ | EXISTING | 17 | 0.177 | 0.285
Escala P1 | 20.20.10.40 | Escales d´estructura | Escala | ARQ | EXISTING | 17 | 0.177 | 0.285
Escala P1 | 20.20.10.40 | Escales d´estructura | Escala | ARQ | EXISTING | 5 | 0.2 | 0.32
Peldaño final | 20.20.10.40 | Escales d´estructura | Escala | ARQ | NEW | 5 | 0.2 | 0.32 | PredefinedType: STRAIGHT_RUN_STAIR; Material: *varios*; Pset_StairCommon - RequiredHeadroom: 2 m; WalkingLineOffset: 0.55 m; TreadLengthAtOffset: 0.32 m; NosingLength: 0 m; TreadLengthAtInnerSide: 0.1 m; NumberOfTreads: 5
Peldaño final | 20.20.10.40 | Escales d´estructura | Escala | ARQ | EXISTING | 17 | 0.168 | 0.285 | PredefinedType: TWO_QUARTER_TURN_STAIR; Material: *varios*; Pset_StairCommon - RequiredHeadroom: 2 m; WalkingLineOffset: 0.585 m; TreadLengthAtOffset: 0.285 m; WaistThickness: 0.17 m; NosingLength: 0 m; TreadLengthAtInnerSide: 0.1 m; NumberOfTreads: 17
Escalera |  |  |  |  |  | 7 | 0.186 | 0.3 | Pset_StairCommon - RequiredHeadroom: 2 m; WalkingLineOffset: 0.9 m; TreadLengthAtOffset: 0.3 m; WaistThickness: 0.17 m; NosingLength: 0 m; TreadLengthAtInnerSide: 0.1 m; NumberOfTreads: 7
Escala PB | 20.20.10.40 | Escales d´estructura | Escala | ARQ | EXISTING | 4 | 0.173 | 0.3
Peldaño final | 20.20.10.40 | Escales d´estructura | Escala | ARQ | EXISTING | 16 | 0.209 | 0.285 | PredefinedType: USERDEFINED; Material: *varios*; Pset_StairCommon - RequiredHeadroom: 2 m; WalkingLineOffset: 0.6 m; TreadLengthAtOffset: 0.285 m; WaistThickness: 0.17 m; NosingLength: 0 m; TreadLengthAtInnerSide: 0.1 m; NumberOfTreads: 16
Escala PB | 20.20.10.40 | Escales d´estructura | Escala | ARQ | EXISTING | 4 | 0.185 | 0.37
3 x  | 30.40.10.10 | Graons exteriors | Graons | ARQ | EXISTING
Escala PS-1 | 20.20.10.40 | Escales d´estructura | Escala | ARQ | EXISTING | 18 | 0.193 | 0.3
Peldaño final | 20.20.10.40 | Escales d´estructura | Escala | ARQ | EXISTING | 16 | 0.217 | 0.3 | PredefinedType: USERDEFINED; Material: *varios*; Pset_StairCommon - RequiredHeadroom: 2 m; WalkingLineOffset: 0.575 m; TreadLengthAtOffset: 0.3 m; WaistThickness: 0.17 m; NosingLength: 0 m; TreadLengthAtInnerSide: 0.1 m; NumberOfTreads: 16
Escala PS-2 | 20.20.10.40 | Escales d´estructura | Escala | ARQ |  | 16 | 0.183 | 0.28
Escala PS-2 | 20.20.10.40 | Escales d´estructura | Escala | ARQ |  | 15 | 0.195 | 0.3

# IfcWall (692)
In: NOU
Name | Material | HCB_I1-CodiGuBIMclass | HCB_I2-DescripcioBIMclass | HCB_I3-TipusNom | HCB_I4-Subsistema | Status
3 x Mur PSC | layer 0.3 m | 20.20.10.30 | Murs Estructurals | Mur | ARQ | EXISTING
8 x Mur PSC | layer 0.15 m | 20.20.10.30 | Murs Estructurals | Mur | ARQ | EXISTING
Mur PSC | layer 0.16 m | 20.20.10.30 | Murs Estructurals | Mur | ARQ | EXISTING
Mur PSC | layer 0.35 m | 20.20.10.30 | Murs Estructurals | Mur | ARQ | EXISTING
Mur PSC |  | 20.20.10.30 | Murs Estructurals | Mur | ARQ | EXISTING
2 x Evans PSC | layer 0.15 m | 40.10.10.10 | Envans | Envans | ARQ | EXISTING
Evans PSC | layer 0.1 m | 40.10.10.10 | Envans | Envans | ARQ | EXISTING
Evans PSC | layer 0.17 m | 40.10.10.10 | Envans | Envans | ARQ | EXISTING
Evans PSC | layer 0.18 m | 40.10.10.10 | Envans | Envans | ARQ | EXISTING
2 x Evans PSC | layer 0.06 m | 40.10.10.10 | Envans | Envans | ARQ | EXISTING
Evans PSC | layer 0.0599922 m | 40.10.10.10 | Envans | Envans | ARQ | EXISTING
 | layer 0.15 m |  |  |  |  | EXISTING
 | layer 0.17 m |  |  |  |  | EXISTING
Façana nord-oest PSC | layer 0.36 m | 30.10.10.10 | Façana in situ | Façana | ARQ | EXISTING
Evans PSC | layer 0.41 m | 40.10.10.10 | Envans | Envans | ARQ | EXISTING
Façana sur-est PSC | layer 0.33 m | 30.10.10.10 | Façanes in situ | Façana | ARQ | EXISTING
Evans PSC | layer 0.32 m | 40.10.10.10 | Envans | Envans | ARQ | EXISTING
Evans PSC | layer 0.33 m | 40.10.10.10 | Envans | Envans | ARQ | EXISTING
18 x Evans P5 | layer 0.1 m | 40.10.10.10 | Envans | Envans | ARQ | EXISTING
8 x Evans P5 | layer 0.15 m | 40.10.10.10 | Envans | Envans | ARQ | EXISTING
Evans P5 | layer 0.03 m | 40.10.10.10 | Envans | Envans | ARQ | EXISTING
9 x Evans P5 | layer 0.05 m | 40.10.10.10 | Envans | Envans | ARQ | EXISTING
2 x Evans P5 |  | 40.10.10.10 | Envans | Envans | ARQ | EXISTING
Evans P5 | layer 0.17 m | 40.10.10.10 | Envans | Envans | ARQ | EXISTING
Evans P5 | layer 0.11 m | 40.10.10.10 | Envans | Envans | ARQ | EXISTING
9 x Mampara P5 | layer 0.05 m | 40.10.10.20 | Mampares | Mampara | ARQ | EXISTING
Mampara P5 | layer 0.1 m | 40.10.10.20 | Mampares | Mampara | ARQ | EXISTING
Evans P5 | layer 0.27 m | 40.10.10.10 | Envans | Envans | ARQ | EXISTING
Evans P5 | layer 0.23 m | 40.10.10.10 | Envans | Envans | ARQ | EXISTING
Façana nord-oest P5 | layer 0.54999 m | 30.10.10.10 | Façana in situ | Façana | ARQ | EXISTING
Evans P5 | layer 0.16 m | 40.10.10.10 | Envans | Envans | ARQ | EXISTING
Mur P5 | layer 0.27 m | 20.20.10.30 | Murs Estructurals | Mur | ARQ | EXISTING
3 x Façana sur-est P5 | layer 0.62 m | 30.10.10.10 | Façana in situ | Façana | ARQ | EXISTING
Façana sur-est P5 | layer 0.2 m | 30.10.10.10 | Façana in situ | Façana | ARQ | EXISTING
4 x Mampara P5 | layer 0.1 m | 40.10.10.20 | Mampares | Mampara | ARQ | NEW
8 x Evans PA | layer 0.03 m | 40.10.10.10 | Envans | Envans | ARQ | EXISTING
13 x Evans PA | layer 0.025 m | 40.10.10.10 | Envans | Envans | ARQ | EXISTING
Evans P5 | layer 0.17 m | 40.10.10.10 | Envans | Envans | ARQ | NEW
14 x Evans P4 | layer 0.1 m | 40.10.10.10 | Envans | Envans | ARQ | EXISTING
8 x Evans P4 | layer 0.15 m | 40.10.10.10 | Envans | Envans | ARQ | EXISTING
3 x Evans P4 | layer 0.07 m | 40.10.10.10 | Envans | Envans | ARQ | EXISTING
9 x Evans P4 | layer 0.05 m | 40.10.10.10 | Envans | Envans | ARQ | EXISTING
Evans P4 |  | 40.10.10.10 | Envans | Envans | ARQ | EXISTING
8 x Mampara P4 | layer 0.05 m | 40.10.10.20 | Mampares | Mampara | ARQ | EXISTING
Mampara P4 | layer 0.03 m | 40.10.10.20 | Mampares | Mampara | ARQ | EXISTING
Mampara P4 |  | 40.10.10.20 | Mampares | Mampara | ARQ | EXISTING
Evans P4 | layer 0.17 m | 40.10.10.10 | Envans | Envans | ARQ | EXISTING
Evans P4 | layer 0.23 m | 40.10.10.10 | Envans | Envans | ARQ | EXISTING
Evans P4 | layer 0.27 m | 40.10.10.10 | Envans | Envans | ARQ | EXISTING
Evans P4 | layer 0.16 m | 40.10.10.10 | Envans | Envans | ARQ | EXISTING
Mur P4 | layer 0.27 m | 20.20.10.30 | Murs Estructurals | Mur | ARQ | EXISTING
Façana nord-oest P4 | layer 0.549997 m | 30.10.10.10 | Façana in situ | Façana | ARQ | EXISTING
Façana sur-est P4 | layer 0.62 m | 30.10.10.10 | Façana in situ | Façana | ARQ | EXISTING
3 x Evans P4 | layer 0.1 m | 40.10.10.10 | Envans | Envans | ARQ | NEW
Evans P4 | layer 0.17 m | 40.10.10.10 | Envans | Envans | ARQ | NEW
4 x Mampara P4 | layer 0.1 m | 40.10.10.20 | Mampares | Mampara | ARQ | NEW
14 x Evans P3 | layer 0.1 m | 40.10.10.10 | Envans | Envans | ARQ | EXISTING
9 x Evans P3 | layer 0.15 m | 40.10.10.10 | Envans | Envans | ARQ | EXISTING
9 x Evans P3 | layer 0.05 m | 40.10.10.10 | Envans | Envans | ARQ | EXISTING
Evans P3 | layer 0.3 m | 40.10.10.10 | Envans | Envans | ARQ | EXISTING
9 x Mampara P3 | layer 0.05 m | 40.10.10.20 | Mampares | Mampara | ARQ | EXISTING
Evans P3 | layer 0.17 m | 40.10.10.10 | Envans | Envans | ARQ | EXISTING
2 x Evans P3 | layer 0.18 m | 40.10.10.10 | Envans | Envans | ARQ | EXISTING
Evans P3 | layer 0.23 m | 40.10.10.10 | Envans | Envans | ARQ | EXISTING
Evans P3 | layer 0.27 m | 40.10.10.10 | Envans | Envans | ARQ | EXISTING
Evans P3 | layer 0.16 m | 40.10.10.10 | Envans | Envans | ARQ | EXISTING
Mur P3 | layer 0.27 m | 20.20.10.30 | Murs Estructurals | Mur | ARQ | EXISTING
Façana nord-oest P3 | layer 0.55 m | 30.10.10.10 | Façana in situ | Façana | ARQ | EXISTING
Façana sur-est P3 | layer 0.62 m | 30.10.10.10 | Façana in situ | Façana | ARQ | EXISTING
4 x Mampara P3 | layer 0.1 m | 40.10.10.20 | Mampares | Mampara | ARQ | NEW
13 x Evans P3 | layer 0.1 m | 40.10.10.10 | Envans | Envans | ARQ | NEW
Evans P3 | layer 0.17 m | 40.10.10.10 | Envans | Envans | ARQ | NEW
9 x Evans P2 | layer 0.05 m | 40.10.10.10 | Envans | Envans | ARQ | EXISTING
8 x Evans P2 | layer 0.15 m | 40.10.10.10 | Envans | Envans | ARQ | EXISTING
12 x Evans P2 | layer 0.1 m | 40.10.10.10 | Envans | Envans | ARQ | EXISTING
Evans P2 | layer 0.17 m | 40.10.10.10 | Envans | Envans | ARQ | EXISTING
Evans P2 |  | 40.10.10.10 | Envans | Envans | ARQ | EXISTING
Evans P2 | layer 0.101814 m | 40.10.10.10 | Envans | Envans | ARQ | EXISTING
Evans P2 | layer 0.09 m | 40.10.10.10 | Envans | Envans | ARQ | EXISTING
Mampara P2 | layer 0.07 m | 40.10.10.20 | Mampares | Mampara | ARQ | EXISTING
8 x Mampara P2 | layer 0.05 m | 40.10.10.20 | Mampares | Mampara | ARQ | EXISTING
Mampara P2 |  | 40.10.10.20 | Mampares | Mampara | ARQ | EXISTING
11 x Envans P1 | layer 0.05 m | 40.10.10.10 | Evans | Evans | ARQ | EXISTING
Evans P2 | layer 0.27 m | 40.10.10.10 | Envans | Envans | ARQ | EXISTING
Evans P2 | layer 0.23 m | 40.10.10.10 | Envans | Envans | ARQ | EXISTING
Mur P2 | layer 0.28 m | 20.20.10.30 | Murs Estructurals | Mur | ARQ | EXISTING
Façana sur-est P2 | layer 0.62 m | 30.10.10.10 | Façana in situ | Façana | ARQ | EXISTING
Façana nord-oest P2 | layer 0.55 m | 30.10.10.10 | Façana in situ | Façana | ARQ | EXISTING
Evans P2 | layer 0.16 m | 40.10.10.10 | Envans | Envans | ARQ | EXISTING
8 x Evans P2 | layer 0.1 m | 40.10.10.10 | Envans | Envans | ARQ | NEW
11 x Mampara P2 | layer 0.1 m | 40.10.10.20 | Mampares | Mampara | ARQ | NEW
Evans P2 | layer 0.15 m | 40.10.10.10 | Envans | Envans | ARQ | NEW
3 x Envans P1 | layer 0.07 m | 40.10.10.10 | Evans | Evans | ARQ | EXISTING
13 x Envans P1 | layer 0.1 m | 40.10.10.10 | Evans | Evans | ARQ | EXISTING
10 x Envans P1 | layer 0.15 m | 40.10.10.10 | Evans | Evans | ARQ | EXISTING
Mampara P1 | layer 0.07 m | 40.10.10.20 | Mampares | Mampara | ARQ | EXISTING
8 x Mampara P1 | layer 0.05 m | 40.10.10.20 | Mampares | Mampara | ARQ | EXISTING
2 x Envans P1 |  | 40.10.10.10 | Evans | Evans | ARQ | EXISTING
2 x Envans P1 | layer 0.17 m | 40.10.10.10 | Evans | Evans | ARQ | EXISTING
Envans P1 | layer 0.12 m | 40.10.10.10 | Evans | Evans | ARQ | EXISTING
Envans P1 | layer 0.23 m | 40.10.10.10 | Evans | Evans | ARQ | EXISTING
Envans P1 | layer 0.27 m | 40.10.10.10 | Evans | Evans | ARQ | EXISTING
Envans P1 | layer 0.75 m | 40.10.10.10 | Evans | Evans | ARQ | EXISTING
Envans P1 | layer 0.4 m | 40.10.10.10 | Evans | Evans | ARQ | EXISTING
Envans P1 | layer 0.3 m | 40.10.10.10 | Evans | Evans | ARQ | EXISTING
Mur P1 | layer 0.28 m | 20.20.10.30 | Murs Estructurals | Mur | ARQ | EXISTING
Façana sur-est P1 | layer 0.62 m | 30.10.10.10 | Façana in situ | Façana | ARQ | EXISTING
3 x Façana nord-oest P1 | layer 0.55 m | 30.10.10.10 | Façana in situ | Façana | ARQ | EXISTING
15 x Mampara P1 | layer 0.1 m | 40.10.10.20 | Mampares | Mampara | ARQ | NEW
12 x Envans P1 | layer 0.1 m | 40.10.10.10 | Evans | Evans | ARQ | NEW
Envans P1 | layer 0.17 m | 40.10.10.10 | Evans | Evans | ARQ | NEW
24 x Evans PA | layer 0.1 m | 40.10.10.10 | Envans | Envans | ARQ | EXISTING
4 x Evans PA | layer 0.05 m | 40.10.10.10 | Envans | Envans | ARQ | EXISTING
4 x Evans PA | layer 0.07 m | 40.10.10.10 | Envans | Envans | ARQ | EXISTING
9 x Evans PA | layer 0.15 m | 40.10.10.10 | Envans | Envans | ARQ | EXISTING
Evans PA | layer 0.11 m | 40.10.10.10 | Envans | Envans | ARQ | EXISTING
2 x Evans PA | layer 0.17 m | 40.10.10.10 | Envans | Envans | ARQ | EXISTING
Evans PA | layer 0.2 m | 40.10.10.10 | Envans | Envans | ARQ | EXISTING
Evans PA | layer 0.12 m | 40.10.10.10 | Envans | Envans | ARQ | EXISTING
2 x Mur PA | layer 0.4 m | 20.20.10.30 | Murs Estructurals | Mur | ARQ | EXISTING
Evans PA | layer 0.22 m | 40.10.10.10 | Envans | Envans | ARQ | EXISTING
Mampara PA | layer 0.11 m | 40.10.10.20 | Mampares | Mampara | ARQ | EXISTING
3 x Evans PA | layer 0.13 m | 40.10.10.10 | Envans | Envans | ARQ | EXISTING
Mur PA | layer 0.55 m | 20.20.10.30 | Murs Estructurals | Mur | ARQ | EXISTING
2 x Evans PA |  | 40.10.10.10 | Envans | Envans | ARQ | EXISTING
2 x Evans PA | layer 0.32 m | 40.10.10.10 | Envans | Envans | ARQ | EXISTING
Façana sur-est PA |  | 30.10.10.10 | Façana in situ | Façana | ARQ | EXISTING
7 x Evans PA | layer 0.1 m | 40.10.10.10 | Envans | Envans | ARQ | NEW
3 x Evans PA | layer 0.15 m | 40.10.10.10 | Envans | Envans | ARQ | NEW
3 x Evans PB |  | 40.10.10.10 | Evans | Envans | ARQ | EXISTING
16 x Envans PB | layer 0.15 m | 40.10.10.10 | Evans | Evans | ARQ | EXISTING
26 x Envans PB | layer 0.1 m | 40.10.10.10 | Evans | Evans | ARQ | EXISTING
6 x Envans PB | layer 0.05 m | 40.10.10.10 | Evans | Evans | ARQ | EXISTING
7 x Envans PB | layer 0.12 m | 40.10.10.10 | Evans | Evans | ARQ | EXISTING
3 x Envans PB | layer 0.06 m | 40.10.10.10 | Evans | Evans | ARQ | EXISTING
Envans PB | layer 0.16 m | 40.10.10.10 | Evans | Evans | ARQ | EXISTING
Envans PB | layer 0.07 m | 40.10.10.10 | Evans | Evans | ARQ | EXISTING
2 x Envans PB | layer 0.17 m | 40.10.10.10 | Evans | Evans | ARQ | EXISTING
8 x Envans PB | layer 0.03 m | 40.10.10.10 | Evans | Evans | ARQ | EXISTING
Envans PB | layer 0.18 m | 40.10.10.10 | Evans | Evans | ARQ | EXISTING
Mampara PB | layer 0.07 m | 40.10.10.20 | Mampares | Mampara | ARQ | EXISTING
3 x Mampara PB | layer 0.06 m | 40.10.10.20 | Mampares | Mampara | ARQ | EXISTING
4 x Mampara PB | layer 0.03 m | 40.10.10.20 | Mampares | Mampara | ARQ | EXISTING
5 x Porta PB | layer 0.06 m | 40.10.10.40 | Fusteria interior | FUS_Porta | ARQ | EXISTING
Mampara PB | layer 0.06 m | 40.10.10.20 | Mampares | Mampara | ARQ | NEW
Envans PB | layer 0.170107 m | 40.10.10.10 | Evans | Evans | ARQ | EXISTING
Envans PB | layer 0.22 m | 40.10.10.10 | Evans | Evans | ARQ | EXISTING
2 x Mur PB | layer 0.36 m | 20.20.10.30 | Murs Estructurals | Mur | ARQ | EXISTING
Mur PB | layer 0.55 m | 20.20.10.30 | Murs Estructurals | Mur | ARQ | EXISTING
Façana sur-est PB | layer 0.62 m | 30.10.10.10 | Façana in situ | Façana | ARQ | EXISTING
13 x Envans PB | layer 0.1 m | 40.10.10.10 | Evans | Evans | ARQ | NEW
Mampara PB | layer 0.0999998 m | 40.10.10.20 | Mampares | Mampara | ARQ | NEW
3 x Mampara PB | layer 0.1 m | 40.10.10.20 | Mampares | Mampara | ARQ | NEW
Envans PB | layer 0.12 m | 40.10.10.10 | Evans | Evans | ARQ | NEW
Envans PB |  | 40.10.10.10 | Evans | Evans | ARQ | EXISTING
8 x Envans PB | layer 0.05 m, layer 0.07 m | 40.10.10.10 | Evans | Evans | ARQ | NEW
Evans P-1 | layer 0.22 m | 40.10.10.10 | Evans | Evans | ARQ | EXISTING
30 x Evans P-1 | layer 0.15 m | 40.10.10.10 | Evans | Evans | ARQ | EXISTING
14 x Evans P-1 | layer 0.1 m | 40.10.10.10 | Evans | Evans | ARQ | EXISTING
Evans P-1 |  | 40.10.10.10 | Evans | Evans | ARQ | EXISTING
Evans P-1 | layer 0.18 m | 40.10.10.10 | Evans | Evans | ARQ | EXISTING
2 x Evans P-1 | layer 0.46 m | 40.10.10.10 | Evans | Evans | ARQ | EXISTING
Mur PS-1 | layer 0.54 m | 20.20.10.30 | Murs Estructurals | Mur | ARQ | EXISTING
2 x Mur PS-1 | layer 1.34 m | 20.20.10.30 | Murs Estructurals | Mur | ARQ | EXISTING
Evans P-1 | layer 0.13 m | 40.10.10.10 | Evans | Evans | ARQ | EXISTING
Mur PS-1 | layer 0.804783 m | 20.10.30.10 | Murs de contenció | Mur de contenció | ARQ | EXISTING
Mur PS-1 | layer 0.62 m | 20.10.30.10 | Murs de contenció | Mur de contenció | ARQ | EXISTING
Evans P-1 | layer 0.3 m | 40.10.10.10 | Evans | Evans | ARQ | EXISTING
Mur PS-1 | layer 0.25 m | 20.20.10.30 | Murs Estructurals | Mur | ARQ | EXISTING
Mur PS-1 | layer 0.5 m | 20.20.10.30 | Murs Estructurals | Mur | ARQ | EXISTING
2 x Evans P-1 | layer 0.15 m | 40.10.10.10 | Evans | Evans | ARQ | NEW
2 x Envans PS-1 | layer 0.05 m, layer 0.07 m | 40.10.10.10 | Evans | Evans | ARQ | NEW
25 x Evans PS-2 | layer 0.15 m | 40.10.10.10 | Envans | Envans | ARQ | EXISTING
2 x Evans PS-2 | layer 0.05 m | 40.10.10.10 | Envans | Envans | ARQ | EXISTING
Evans PS-2 | layer 0.1 m | 40.10.10.10 | Envans | Envans | ARQ | EXISTING
Evans PS-2 | layer 0.18 m | 40.10.10.10 | Envans | Envans | ARQ | EXISTING
Mur PS-2 | layer 0.95 m | 20.20.10.30 | Murs Estructurals | Mur | ARQ | EXISTING
Evans PS-2 | layer 0.13 m | 40.10.10.10 | Envans | Envans | ARQ | EXISTING | Description: Envans
Evans PS-2 | layer 0.2 m | 40.10.10.10 | Envans | Envans | ARQ | EXISTING
Mur PS-2 | layer 1.34 m | 20.20.10.30 | Murs Estructurals | Mur | ARQ | EXISTING
Mur PS-2 | layer 0.62 m | 20.10.30.10 | Murs de contenció | Mur de contenció | ARQ | EXISTING
Porta PS-2 | layer 0.05 m | 40.10.10.40 | Fusteria interior | FUS_Porta | ARQ | EXISTING
Evans PS-2 | layer 0.16 m | 40.10.10.10 | Envans | Envans | ARQ | EXISTING
Mur PS-2 | layer 0.29 m | 20.20.10.30 | Murs Estructurals | Mur | ARQ | EXISTING
2 x Evans PS-2 | layer 0.15 m | 40.10.10.10 | Envans | Envans | ARQ | NEW

# IfcWindow (19)
In: NOU
PredefinedType: WINDOW; PartitioningType: USERDEFINED
AllplanQuantities - HeightWindowSillOutside: 0; HeightWindowSillInside: 0; OffsetOpeningBottom: 0; OffsetOpeningTop: 0; OffsetOpeningLeft: 0; OffsetOpeningRight: 0; DeductionOpeningBottom: 70; DeductionOpeningLeft: 70; DeductionOpeningRight: 70; DeductionOpeningTop: 70
Name | OverallHeight (m) | OverallWidth (m) | GlassSurface | HCB_I1-CodiGuBIMclass | HCB_I2-DescripcioBIMclass | HCB_I3-TipusNom | HCB_I4-Subsistema | Status
Finestra PSC | 0.8 | 0.6356 | 0.327096 | 30.10.20.10 | Finestres de façanes | FUS_Finestra | ARQ | EXISTING
Finestra PSC | 0.4 | 1.13881 | 0.25969 | 30.10.20.10 | Finestres de façanes | FUS_Finestra | ARQ | EXISTING
Finestra PSC | 0.4 | 0.59 | 0.117 | 30.10.20.10 | Finestres de façanes | FUS_Finestra | ARQ | EXISTING
Finestra PSC | 0.8 | 4.16 | 2.6532 | 30.10.20.10 | Finestres de façanes | FUS_Finestra | ARQ | EXISTING
Finestra PSC | 1 | 2.44 | 1.978 | 30.10.20.10 | Finestres de façanes | FUS_Finestra | ARQ | EXISTING
Finestra PSC | 0.8 | 0.4 | 0.1716 | 30.10.20.10 | Finestres de façanes | FUS_Finestra | ARQ | EXISTING
Finestra P5 | 1.2 | 1.24 | 1.166 | 40.10.10.40 | Fusteria interior | FUS_Finestra | ARQ | EXISTING
Finestra P4 | 1.2 | 1.24 | 1.166 | 40.10.10.40 | Fusteria interior | FUS_Finestra | ARQ | EXISTING
2 x Finestra P1 | 1.2 | 1.24 | 1.166 | 40.10.10.40 | Fusteria interior | FUS_Finestra | ARQ | EXISTING
Finestra P2 | 1.2 | 1.24 | 1.166 | 40.10.10.40 | Fusteria interior | FUS_Finestra | ARQ | EXISTING
7 x Ventana | 0.4 | 0.49 | 0 |  |  |  |  | EXISTING
Porta PB | 2.38 | 2.52997 | 5.0709 | 30.10.20.20 | Portes de façanes | Portes de façanes | ARQ | NEW
